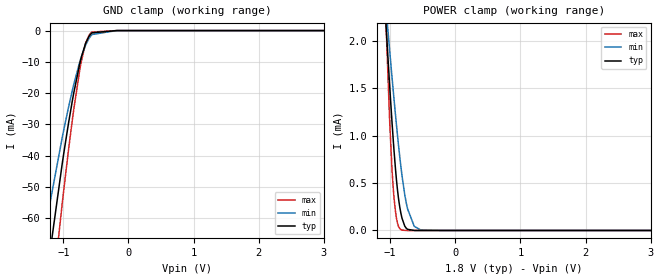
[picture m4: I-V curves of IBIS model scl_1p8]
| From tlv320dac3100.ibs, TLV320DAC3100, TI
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|   scl_1p8 Model
[Model]   scl_1p8
Model_type   Input
Vinl = 0.54
Vinh = 1.26
|   typ   min   max
|   (nom PVT)   (fast PVT)   (slow PVT)
C_comp   1.188e-12   1.178e-12   1.188e-12
| Where nom  PVT is Nominal Process, 1.8V, 27C
|   Fast PVT is Strong Process,  1.98V, -40C
|   Slow PVT is Weak Process,   1.62V, 125C
[Model spec]
Vinl   0.54   0.486   0.594
Vinh   1.26   1.134   1.386
[Voltage Range]   1.8   1.62   1.98
|Junction Temperature
[Temperature Range]   27   125   -40
[Power Clamp Reference]   1.8   1.62   1.98
[GND Clamp Reference]   0   0   0
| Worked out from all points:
|   GND clamp passes 1 mA (typ) near -0.57 V on its own axis
|   POWER clamp passes 1 mA (typ) near -0.96 V on its own axis
[GND Clamp]
|   Voltage   I(typ)   I(min)   I(max)
-1.8V     -265.1mA   -154.4mA   -381.7mA
-1.349V   -93.56mA   -71.94mA   -120mA
-1.252V   -78.05mA   -60.45mA   -100.7mA
-1.016V   -42.44mA   -34.1mA    -55.13mA
-920.3mV  -29.65mA   -24.57mA   -38.23mA
-859.5mV  -22.23mA   -18.98mA   -28.29mA
-747mV    -10.58mA   -9.981mA   -12.55mA
-657.5mV  -4.082mA   -4.619mA   -4.078mA
-606.1mV  -1.843mA   -2.515mA   -1.515mA
-558mV    -715.8uA   -1.245mA   -464.5uA
-180mV    0A         -211.6nA   0A
3.6V      0A         0A         0A
[POWER Clamp]
|   Voltage   I(typ)   I(min)   I(max)
-1.8V     11.74mA    8.748mA    19.35mA
-1.075V   2.291mA    2.431mA    2.403mA
-1.058V   2.089mA    2.292mA    2.061mA
-1.004V   1.481mA    1.865mA    1.095mA
-972.4mV  1.145mA    1.619mA    648.1uA
-948.6mV  911.8uA    1.439mA    403.5uA
-901.8mV  521.3uA    1.1mA      123.2uA
-835.2mV  180.5uA    670.8uA    9.313uA
-732.4mV  12.01uA    226.7uA    83.67nA
-630.4mV  330.9nA    44.02uA    0A
-528.3mV  0A         3.711uA    0A
3.6V      0A         0A         0A
